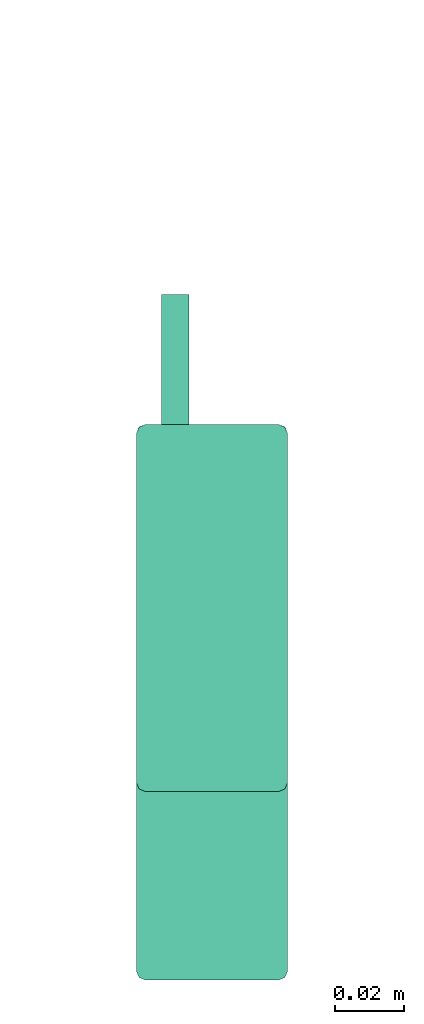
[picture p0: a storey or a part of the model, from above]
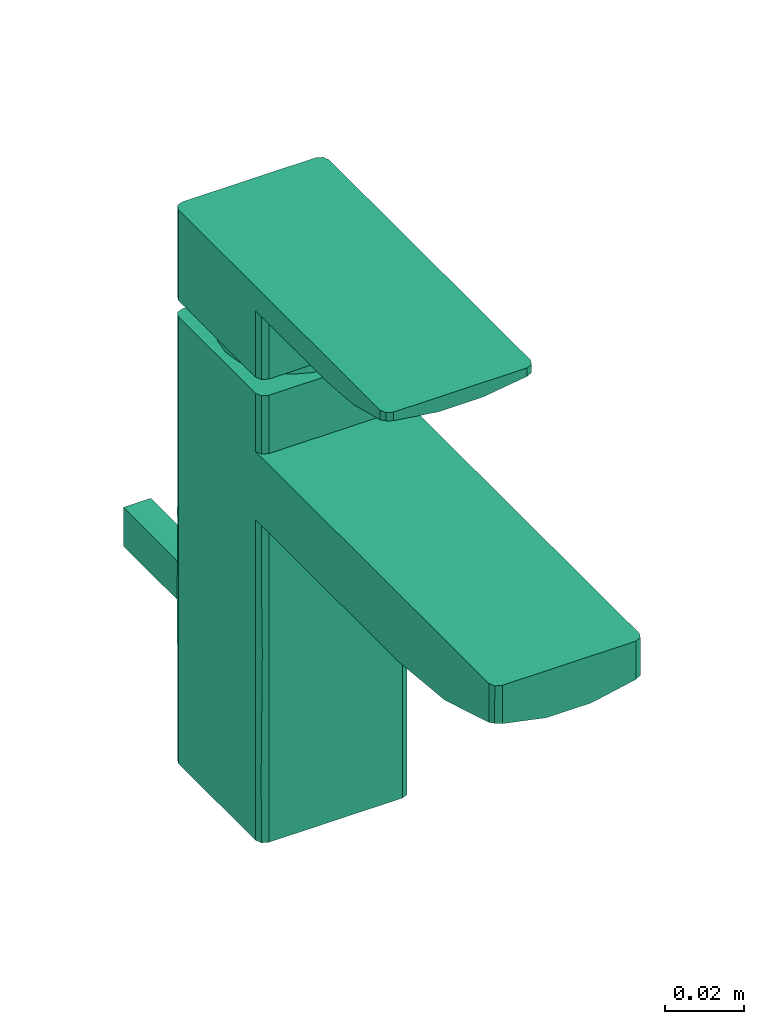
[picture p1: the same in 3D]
Properties of the parts of a building model (IFC2X3)

# File
Description: ViewDefinition [CoordinationView_V2.0]
File name: 0001
Time: 2023-08-21T11:10:22
Written by: The EXPRESS Data Manager Version 5.02.0100.07 : 28 Aug 2013
Made in: 21.1.1.109 - Exporter 21.1.1.109 - Alternate UI 21.1.1.109
Comment: STEP Physical File produced by: The EXPRESS Data Manager Version 5.02.0100.07 : 28 Aug 2013 * Module: EDMstepFileFactory/EDMstandAlone * Creation date: Mon Aug 21 11:10:22 2023 * Host: DESKTOP-H3C3U9I * Database: C:\Users\nawap\AppData\Local\Temp\0f40046e-215a-462d-bf0d-38415a8519d0\396ff460-bbe9-451c-9add-c3cdb93be2ab\ifc * Database version: 5507 * Database creation date: Mon Aug 21 11:10:21 2023 * Schema: IFC2X3 * Model: DataRepository.ifc * Model creation date: Mon Aug 21 11:10:22 2023 * Header model: DataRepository.ifc_HeaderModel * Header model creation date: Mon Aug 21 11:10:22 2023 * EDMuser: sdai-user * EDMgroup: sdai-group * License ID and type: 5605 : Permanent license. Expiry date: * EDMstepFileFactory options: 020000

# IfcProject, 0001
LongName: Project Name; Phase: Project Status

# IfcSite, Default
RefLatitude: 42, 21, 31, 181945; RefLongitude: -71, -3, -24, -263305; RefElevation: 0 mm
Pset_ProductRequirements - Category: Project Information

# IfcBuilding
Pset_ProductRequirements - Category: Project Information
Pset_BuildingCommon - NumberOfStoreys: 1

# IfcBuildingStorey: Level:8mm Head, Level 1
LongName: Level 1; Elevation: 0 mm
Pset_AirSideSystemInformation - Name: Level 1
Pset_ProductRequirements - Name: Level 1; Category: Levels

# IfcDistributionPort, Port_308141
Description: Flow; FlowDirection: SOURCE

# IfcFlowTerminal: FFAS1301-101AL0BT0_REVIT:Acacia E SH SL basin mixer, FFAS1301-101AL0BT0_REVIT:Acacia E SH SL basin mixer:308141
In: Level 1
Type - Material: Brushed Hard Graphite
Type - Pset_DuctConnection - ConnectionType: G1/2 G1/2
Type - Pset_ManufacturerTypeInformation - Manufacturer: American Standard
Type - Pset_PipeConnection - ConnectionType: G1/2 G1/2
Type - Pset_ProductRequirements - Category: Plumbing Fixtures
Type - Pset_QuantityTakeOff - Reference: Acacia E SH SL basin mixer
Pset_DistributionFlowElementCommon - Reference: Acacia E SH SL basin mixer; sets with these values: 2
Pset_DuctConnection - sets with these values: 2

# IfcWallStandardCase: Basic Wall:Generic - 200mm, Basic Wall:Generic - 200mm:298090
In: Level 1
Type - PredefinedType: STANDARD; Material: Default Wall 200 mm
Type - Pset_ElementShading - Roughness: 914.4 mm
Type - Pset_ProductRequirements - Category: Walls
Type - Pset_QuantityTakeOff - Reference: Generic - 200mm
Type - Pset_ReinforcementBarPitchOfWall - Reference: Generic - 200mm
Type - Pset_WallCommon - Reference: Generic - 200mm; IsExternal: no
Pset_QuantityTakeOff - sets with these values: 2
Pset_WallCommon - IsExternal: yes; ExtendToStructure: no; LoadBearing: no
